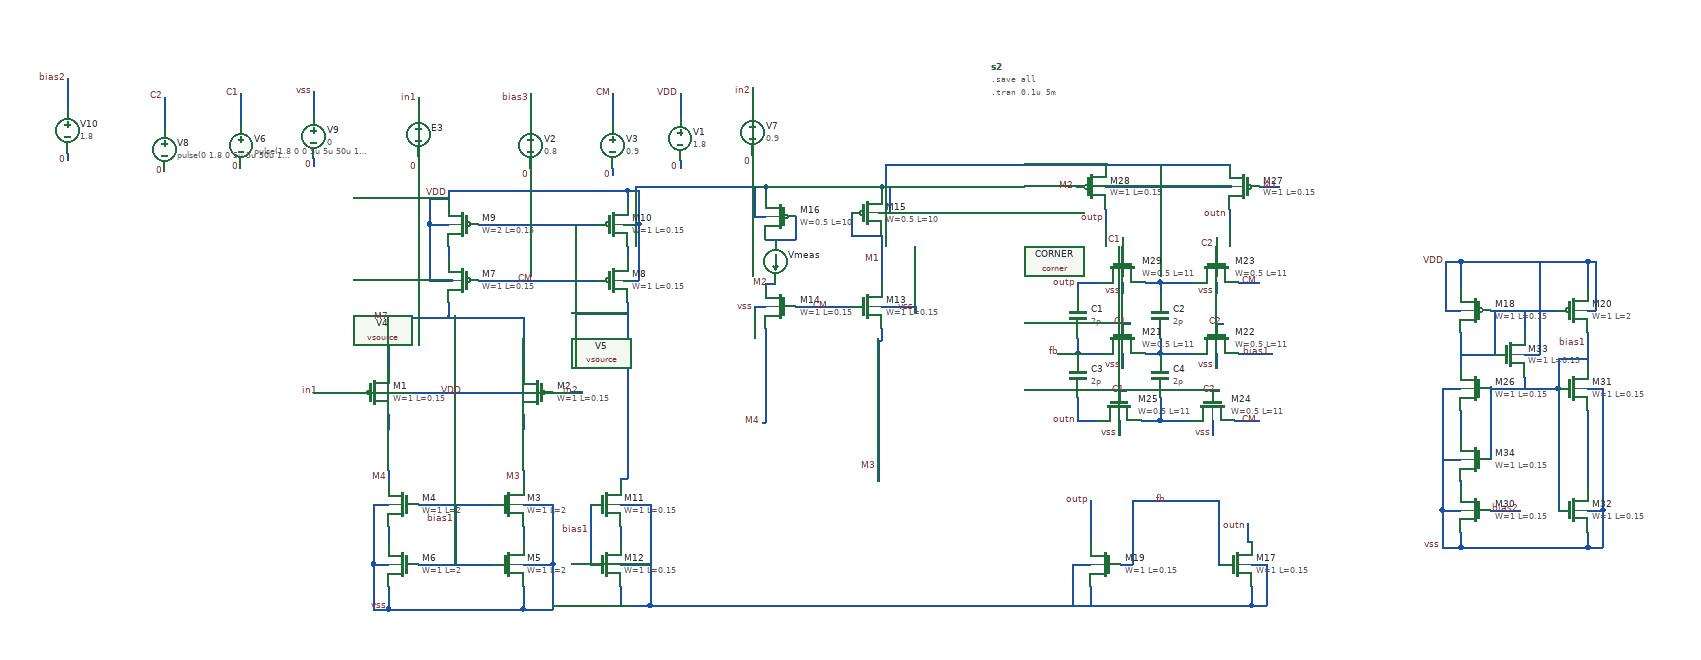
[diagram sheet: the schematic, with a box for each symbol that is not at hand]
v {xschem version=3.1.0 file_version=1.2
}
G {}
K {}
V {}
S {}
E {}
N -190 -670 -190 -660 {
lab=0}
N -390 -660 -390 -650 {
lab=0}
N -390 -760 -390 -720 {
lab=bias3}
N -280 -660 -280 -650 {
lab=0}
N -280 -760 -280 -720 {
lab=CM}
N -190 -760 -190 -730 {
lab=VDD}
N -540 -675 -540 -650 {
lab=0}
N -540 -755 -540 -735 {
lab=in1}
N -92.5 -677.5 -92.5 -667.5 {
lab=0}
N -92.5 -767.5 -92.5 -737.5 {
lab=in2}
N -680 -672.5 -680 -662.5 {
lab=0}
N -680 -762.5 -680 -732.5 {
lab=vss}
N -580 -460 -580 -390 {
lab=M7}
N -580 -460 -400 -460 {
lab=M7}
N -400 -460 -400 -390 {
lab=M7}
N -500 -480 -500 -460 {
lab=M7}
N -540 -210 -440 -210 {
lab=bias1}
N -540 -130 -440 -130 {
lab=bias1}
N -580 -180 -580 -160 {
lab=#net1}
N -400 -180 -400 -160 {
lab=#net2}
N -600 -210 -580 -210 {
lab=vss}
N -600 -210 -600 -130 {
lab=vss}
N -600 -130 -580 -130 {
lab=vss}
N -400 -210 -360 -210 {
lab=vss}
N -360 -210 -360 -130 {
lab=vss}
N -400 -130 -360 -130 {
lab=vss}
N -580 -100 -580 -70 {
lab=vss}
N -580 -70 -400 -70 {
lab=vss}
N -400 -100 -400 -70 {
lab=vss}
N -490 -210 -490 -130 {
lab=bias1}
N -680 -360 -620 -360 {
lab=in1}
N -360 -360 -320 -360 {
lab=in2}
N -600 -130 -600 -80 {
lab=vss}
N -600 -80 -600 -70 {
lab=vss}
N -600 -70 -580 -70 {
lab=vss}
N -360 -130 -360 -70 {
lab=vss}
N -400 -70 -360 -70 {
lab=vss}
N -580 -330 -580 -310 {
lab=#net3}
N -580 -250 -580 -240 {
lab=M4}
N -580 -255 -580 -250 {
lab=M4}
N -400 -330 -400 -310 {
lab=#net4}
N -400 -250 -400 -240 {
lab=M3}
N -400 -255 -400 -250 {
lab=M3}
N -525 -510 -495 -510 {
lab=VDD}
N -525 -555 -525 -510 {
lab=VDD}
N -460 -510 -300 -510 {
lab=CM}
N -500 -555 -500 -540 {
lab=#net5}
N -460 -585 -300 -585 {
lab=#net6}
N -500 -630 -500 -615 {
lab=VDD}
N -500 -630 -260 -630 {
lab=VDD}
N -260 -630 -260 -615 {
lab=VDD}
N -265 -585 -245 -585 {
lab=VDD}
N -245 -630 -245 -585 {
lab=VDD}
N -260 -630 -245 -630 {
lab=VDD}
N -260 -555 -260 -540 {
lab=#net7}
N -265 -510 -245 -510 {
lab=VDD}
N -245 -585 -245 -510 {
lab=VDD}
N -525 -585 -500 -585 {
lab=VDD}
N -525 -585 -525 -555 {
lab=VDD}
N -525 -620 -525 -585 {
lab=VDD}
N -525 -620 -500 -620 {
lab=VDD}
N -270 -180 -270 -160 {
lab=#net8}
N -270 -100 -270 -75 {
lab=vss}
N -360 -75 -270 -75 {
lab=vss}
N -270 -210 -230 -210 {
lab=vss}
N -230 -210 -230 -75 {
lab=vss}
N -275 -75 -230 -75 {
lab=vss}
N -270 -130 -230 -130 {
lab=vss}
N -310 -210 -310 -130 {
lab=bias1}
N -260 -480 -260 -245 {
lab=#net6}
N -270 -245 -260 -245 {
lab=#net6}
N -270 -245 -270 -240 {
lab=#net6}
N -330 -585 -330 -465 {
lab=#net6}
N -330 -465 -260 -465 {
lab=#net6}
N -75 -445 -75 -440 {
lab=M4}
N 80 -445 80 -430 {
lab=M3}
N -90 -475 -75 -475 {
lab=vss}
N -90 -475 -90 -470 {
lab=vss}
N 80 -475 125 -475 {
lab=vss}
N 125 -475 125 -465 {
lab=vss}
N -35 -475 40 -475 {
lab=CM}
N -35 -595 -35 -565 {
lab=#net9}
N -75 -565 -35 -565 {
lab=#net9}
N -75 -635 -75 -625 {
lab=VDD}
N -75 -635 80 -635 {
lab=VDD}
N 80 -635 80 -630 {
lab=VDD}
N 75 -600 90 -600 {
lab=VDD}
N 90 -635 90 -600 {
lab=VDD}
N 80 -635 90 -635 {
lab=VDD}
N -90 -595 -75 -595 {
lab=VDD}
N -90 -635 -90 -595 {
lab=VDD}
N -90 -635 -75 -635 {
lab=VDD}
N 40 -600 40 -570 {
lab=M1}
N 40 -570 80 -570 {
lab=M1}
N 80 -570 80 -505 {
lab=M1}
N -250 -635 -85 -635 {
lab=VDD}
N -250 -635 -250 -630 {
lab=VDD}
N 75 -430 75 -255 {
lab=M3}
N 75 -430 80 -430 {
lab=M3}
N 75 -255 75 -240 {
lab=M3}
N -75 -440 -75 -325 {
lab=M4}
N -80 -320 -75 -320 {
lab=M4}
N -75 -325 -75 -320 {
lab=M4}
N -580 -360 -395 -360 {
lab=VDD}
N -230 -75 575 -75 {
lab=vss}
N 575 -100 575 -75 {
lab=vss}
N 360 -100 360 -75 {
lab=vss}
N 400 -130 415 -130 {
lab=fb}
N 415 -215 415 -130 {
lab=fb}
N 360 -185 360 -160 {
lab=outp}
N 335 -130 360 -130 {
lab=vss}
N 575 -75 595 -75 {
lab=vss}
N 575 -130 595 -130 {
lab=vss}
N 570 -185 570 -160 {
lab=outn}
N 570 -160 575 -160 {
lab=outn}
N 530 -215 530 -130 {
lab=fb}
N 530 -130 535 -130 {
lab=fb}
N 415 -215 530 -215 {
lab=fb}
N 585 -635 612.5 -635 {
lab=M1}
N 380 -665 545 -665 {
lab=VDD}
N 380 -635 547.5 -635 {
lab=VDD}
N 452.5 -665 452.5 -635 {
lab=VDD}
N 85 -665 382.5 -665 {
lab=VDD}
N 85 -665 85 -635 {
lab=VDD}
N 380 -605 380 -582.5 {
lab=outp}
N 545 -605 545 -585 {
lab=outn}
N -777.5 -760 -777.5 -720 {
lab=C1}
N -880 -755 -880 -715 {
lab=C2}
N -75 -505 -62.5 -505 {
lab=M2}
N 342.5 -432.5 342.5 -412.5 {
lab=fb}
N 452.5 -432.5 452.5 -412.5 {
lab=#net10}
N 342.5 -352.5 342.5 -322.5 {
lab=outn}
N 342.5 -322.5 367.5 -322.5 {
lab=outn}
N 427.5 -322.5 452.5 -322.5 {
lab=#net11}
N 452.5 -352.5 452.5 -322.5 {
lab=#net11}
N 402.5 -412.5 402.5 -392.5 {
lab=vss}
N 432.5 -412.5 452.5 -412.5 {
lab=#net10}
N 342.5 -412.5 372.5 -412.5 {
lab=fb}
N 397.5 -322.5 397.5 -302.5 {
lab=vss}
N 397.5 -362.5 407.5 -362.5 {
lab=C1}
N 402.5 -452.5 412.5 -452.5 {
lab=C1}
N 342.5 -507.5 342.5 -492.5 {
lab=outp}
N 342.5 -507.5 372.5 -507.5 {
lab=outp}
N 432.5 -507.5 452.5 -507.5 {
lab=#net12}
N 452.5 -507.5 452.5 -492.5 {
lab=#net12}
N 402.5 -507.5 402.5 -492.5 {
lab=vss}
N 402.5 -567.5 402.5 -547.5 {
lab=C1}
N 527.5 -412.5 527.5 -392.5 {
lab=vss}
N 522.5 -322.5 522.5 -302.5 {
lab=vss}
N 522.5 -362.5 532.5 -362.5 {
lab=C2}
N 527.5 -452.5 537.5 -452.5 {
lab=C2}
N 527.5 -507.5 527.5 -492.5 {
lab=vss}
N 527.5 -567.5 527.5 -547.5 {
lab=C2}
N 452.5 -322.5 492.5 -322.5 {
lab=#net11}
N 452.5 -412.5 497.5 -412.5 {
lab=#net10}
N 452.5 -507.5 497.5 -507.5 {
lab=#net12}
N 315 -412.5 342.5 -412.5 {
lab=fb}
N 552.5 -322.5 557.5 -322.5 {
lab=CM}
N 557.5 -322.5 585 -322.5 {
lab=CM}
N 557.5 -507.5 585 -507.5 {
lab=CM}
N 557.5 -412.5 577.5 -412.5 {
lab=bias1}
N 577.5 -412.5 602.5 -412.5 {
lab=bias1}
N 595 -130 595 -75 {
lab=vss}
N 335 -130 335 -75 {
lab=vss}
N 360 -215 360 -185 {
lab=outp}
N 855 -535 855 -500 {
lab=VDD}
N 855 -535 1025 -535 {
lab=VDD}
N 1025 -535 1025 -505 {
lab=VDD}
N 1025 -505 1025 -500 {
lab=VDD}
N 1025 -440 1025 -395 {
lab=bias1}
N 1025 -172.5 1025 -152.5 {
lab=vss}
N 855 -152.5 1025 -152.5 {
lab=vss}
N 855 -172.5 855 -152.5 {
lab=vss}
N 855 -440 855 -395 {
lab=#net13}
N 895 -470 985 -470 {
lab=#net13}
N 940 -470 940 -440 {
lab=#net13}
N 900 -470 900 -410 {
lab=#net13}
N 855 -410 900 -410 {
lab=#net13}
N 895 -365 985 -365 {
lab=bias1}
N 940 -380 940 -365 {
lab=bias1}
N 985 -365 985 -260 {
lab=bias1}
N 985 -405 985 -365 {
lab=bias1}
N 985 -405 1025 -405 {
lab=bias1}
N 940 -410 960 -410 {
lab=VDD}
N 960 -535 960 -410 {
lab=VDD}
N 1025 -470 1035 -470 {
lab=VDD}
N 1035 -535 1035 -470 {
lab=VDD}
N 1025 -535 1035 -535 {
lab=VDD}
N 835 -470 855 -470 {
lab=VDD}
N 835 -535 835 -470 {
lab=VDD}
N 835 -535 855 -535 {
lab=VDD}
N 830 -365 855 -365 {
lab=vss}
N 830 -365 830 -260 {
lab=vss}
N 830 -202.5 855 -202.5 {
lab=vss}
N 830 -202.5 830 -152.5 {
lab=vss}
N 830 -152.5 855 -152.5 {
lab=vss}
N 1025 -365 1045 -365 {
lab=vss}
N 1045 -365 1045 -260 {
lab=vss}
N 1025 -202.5 1045 -202.5 {
lab=vss}
N 1045 -202.5 1045 -152.5 {
lab=vss}
N 1025 -152.5 1045 -152.5 {
lab=vss}
N -1010 -680 -1010 -670 {
lab=0}
N -1010 -780 -1010 -740 {
lab=bias2}
N 895 -202.5 935 -202.5 {
lab=bias2}
N 855 -242.5 855 -232.5 {
lab=#net14}
N 830 -260 830 -202.5 {
lab=vss}
N 830 -270 855 -270 {
lab=vss}
N 895 -367.5 895 -270 {
lab=bias1}
N 985 -260 985 -205 {
lab=bias1}
N 1045 -262.5 1045 -202.5 {
lab=vss}
N 1025 -335 1025 -232.5 {
lab=#net15}
N 855 -335 855 -300 {
lab=#net16}
N 985 -205 985 -202.5 {
lab=bias1}
C {devices/vsource.sym} -190 -700 0 0 {name=V1 value=1.8}
C {devices/lab_pin.sym} -190 -660 0 0 {name=p5 sig_type=std_logic lab=0}
C {devices/vsource.sym} -390 -690 0 0 {name=V2 value=0.8}
C {devices/lab_pin.sym} -390 -650 0 0 {name=p9 sig_type=std_logic lab=0}
C {devices/lab_pin.sym} 1025 -425 0 0 {name=p10 sig_type=std_logic lab=bias1}
C {devices/vsource.sym} -280 -690 0 0 {name=V3 value=0.9}
C {devices/lab_pin.sym} -280 -650 0 0 {name=p11 sig_type=std_logic lab=0}
C {devices/lab_pin.sym} -280 -760 0 0 {name=p12 sig_type=std_logic lab=CM}
C {devices/lab_pin.sym} -190 -760 0 0 {name=p16 sig_type=std_logic lab=VDD}
C {sky130_fd_pr/corner.sym} 45 -815 0 0 {name=CORNER only_toplevel=false corner=ss}
C {devices/code_shown.sym} 227.5 -795 0 0 {name=s2 only_toplevel=false value="
.save all
.tran 0.1u 5m
"}
C {devices/lab_pin.sym} -540 -660 0 0 {name=p8 sig_type=std_logic lab=0}
C {devices/lab_pin.sym} -540 -752.5 0 0 {name=p18 sig_type=std_logic lab=in1}
C {devices/vsource_arith.sym} -540 -705 0 0 {name=E3 VOL="'0.9+0.2*cos(2*pi*time*1e3))'"}
C {devices/vsource.sym} -92.5 -707.5 0 0 {name=V7 value=0.9}
C {devices/lab_pin.sym} -92.5 -667.5 0 0 {name=p26 sig_type=std_logic lab=0}
C {devices/lab_pin.sym} -92.5 -762.5 0 0 {name=p20 sig_type=std_logic lab=in2}
C {devices/vsource.sym} -680 -702.5 0 0 {name=V9 value=0}
C {devices/lab_pin.sym} -680 -662.5 0 0 {name=p31 sig_type=std_logic lab=0}
C {devices/lab_pin.sym} -680 -762.5 0 0 {name=p32 sig_type=std_logic lab=vss}
C {sky130_fd_pr/pfet_01v8.sym} -600 -360 0 0 {name=M1
L=0.15
W=1
nf=1
mult=10
ad="'int((nf+1)/2) * W/nf * 0.29'" 
pd="'2*int((nf+1)/2) * (W/nf + 0.29)'"
as="'int((nf+2)/2) * W/nf * 0.29'" 
ps="'2*int((nf+2)/2) * (W/nf + 0.29)'"
nrd="'0.29 / W'" nrs="'0.29 / W'"
sa=0 sb=0 sd=0
model=pfet_01v8
spiceprefix=X
}
C {sky130_fd_pr/pfet_01v8.sym} -380 -360 0 1 {name=M2
L=0.15
W=1
nf=1
mult=10
ad="'int((nf+1)/2) * W/nf * 0.29'" 
pd="'2*int((nf+1)/2) * (W/nf + 0.29)'"
as="'int((nf+2)/2) * W/nf * 0.29'" 
ps="'2*int((nf+2)/2) * (W/nf + 0.29)'"
nrd="'0.29 / W'" nrs="'0.29 / W'"
sa=0 sb=0 sd=0
model=pfet_01v8
spiceprefix=X
}
C {sky130_fd_pr/nfet_01v8.sym} -420 -210 0 0 {name=M3
L=2
W=1
nf=1 
mult=1
ad="'int((nf+1)/2) * W/nf * 0.29'" 
pd="'2*int((nf+1)/2) * (W/nf + 0.29)'"
as="'int((nf+2)/2) * W/nf * 0.29'" 
ps="'2*int((nf+2)/2) * (W/nf + 0.29)'"
nrd="'0.29 / W'" nrs="'0.29 / W'"
sa=0 sb=0 sd=0
model=nfet_01v8
spiceprefix=X
}
C {sky130_fd_pr/nfet_01v8.sym} -560 -210 0 1 {name=M4
L=2
W=1
nf=1 
mult=1
ad="'int((nf+1)/2) * W/nf * 0.29'" 
pd="'2*int((nf+1)/2) * (W/nf + 0.29)'"
as="'int((nf+2)/2) * W/nf * 0.29'" 
ps="'2*int((nf+2)/2) * (W/nf + 0.29)'"
nrd="'0.29 / W'" nrs="'0.29 / W'"
sa=0 sb=0 sd=0
model=nfet_01v8
spiceprefix=X
}
C {sky130_fd_pr/nfet_01v8.sym} -420 -130 0 0 {name=M5
L=2
W=1
nf=1 
mult=1
ad="'int((nf+1)/2) * W/nf * 0.29'" 
pd="'2*int((nf+1)/2) * (W/nf + 0.29)'"
as="'int((nf+2)/2) * W/nf * 0.29'" 
ps="'2*int((nf+2)/2) * (W/nf + 0.29)'"
nrd="'0.29 / W'" nrs="'0.29 / W'"
sa=0 sb=0 sd=0
model=nfet_01v8
spiceprefix=X
}
C {sky130_fd_pr/nfet_01v8.sym} -560 -130 0 1 {name=M6
L=2
W=1
nf=1 
mult=1
ad="'int((nf+1)/2) * W/nf * 0.29'" 
pd="'2*int((nf+1)/2) * (W/nf + 0.29)'"
as="'int((nf+2)/2) * W/nf * 0.29'" 
ps="'2*int((nf+2)/2) * (W/nf + 0.29)'"
nrd="'0.29 / W'" nrs="'0.29 / W'"
sa=0 sb=0 sd=0
model=nfet_01v8
spiceprefix=X
}
C {devices/lab_pin.sym} -500 -625 0 0 {name=p1 sig_type=std_logic lab=VDD}
C {devices/lab_pin.sym} -672.5 -360 0 0 {name=p2 sig_type=std_logic lab=in1}
C {devices/lab_pin.sym} -322.5 -360 0 0 {name=p3 sig_type=std_logic lab=in2}
C {devices/lab_pin.sym} -580 -72.5 0 0 {name=p4 sig_type=std_logic lab=vss}
C {devices/lab_pin.sym} -490 -190 0 0 {name=p6 sig_type=std_logic lab=bias1}
C {devices/vsource.sym} -580 -282.5 0 0 {name=V4 value=0}
C {devices/vsource.sym} -400 -282.5 0 0 {name=V5 value=0}
C {sky130_fd_pr/pfet_01v8.sym} -480 -510 0 1 {name=M7
L=0.15
W=1
nf=1
mult=1
ad="'int((nf+1)/2) * W/nf * 0.29'" 
pd="'2*int((nf+1)/2) * (W/nf + 0.29)'"
as="'int((nf+2)/2) * W/nf * 0.29'" 
ps="'2*int((nf+2)/2) * (W/nf + 0.29)'"
nrd="'0.29 / W'" nrs="'0.29 / W'"
sa=0 sb=0 sd=0
model=pfet_01v8
spiceprefix=X
}
C {sky130_fd_pr/pfet_01v8.sym} -280 -510 0 0 {name=M8
L=0.15
W=1
nf=1
mult=1
ad="'int((nf+1)/2) * W/nf * 0.29'" 
pd="'2*int((nf+1)/2) * (W/nf + 0.29)'"
as="'int((nf+2)/2) * W/nf * 0.29'" 
ps="'2*int((nf+2)/2) * (W/nf + 0.29)'"
nrd="'0.29 / W'" nrs="'0.29 / W'"
sa=0 sb=0 sd=0
model=pfet_01v8
spiceprefix=X
}
C {sky130_fd_pr/pfet_01v8.sym} -480 -585 0 1 {name=M9
L=0.15
W=2
nf=1
mult=1
ad="'int((nf+1)/2) * W/nf * 0.29'" 
pd="'2*int((nf+1)/2) * (W/nf + 0.29)'"
as="'int((nf+2)/2) * W/nf * 0.29'" 
ps="'2*int((nf+2)/2) * (W/nf + 0.29)'"
nrd="'0.29 / W'" nrs="'0.29 / W'"
sa=0 sb=0 sd=0
model=pfet_01v8
spiceprefix=X
}
C {sky130_fd_pr/pfet_01v8.sym} -280 -585 0 0 {name=M10
L=0.15
W=1
nf=1
mult=1
ad="'int((nf+1)/2) * W/nf * 0.29'" 
pd="'2*int((nf+1)/2) * (W/nf + 0.29)'"
as="'int((nf+2)/2) * W/nf * 0.29'" 
ps="'2*int((nf+2)/2) * (W/nf + 0.29)'"
nrd="'0.29 / W'" nrs="'0.29 / W'"
sa=0 sb=0 sd=0
model=pfet_01v8
spiceprefix=X
}
C {sky130_fd_pr/nfet_01v8.sym} -290 -210 0 0 {name=M11
L=0.15
W=1
nf=1 
mult=1
ad="'int((nf+1)/2) * W/nf * 0.29'" 
pd="'2*int((nf+1)/2) * (W/nf + 0.29)'"
as="'int((nf+2)/2) * W/nf * 0.29'" 
ps="'2*int((nf+2)/2) * (W/nf + 0.29)'"
nrd="'0.29 / W'" nrs="'0.29 / W'"
sa=0 sb=0 sd=0
model=nfet_01v8
spiceprefix=X
}
C {sky130_fd_pr/nfet_01v8.sym} -290 -130 0 0 {name=M12
L=0.15
W=1
nf=1 
mult=1
ad="'int((nf+1)/2) * W/nf * 0.29'" 
pd="'2*int((nf+1)/2) * (W/nf + 0.29)'"
as="'int((nf+2)/2) * W/nf * 0.29'" 
ps="'2*int((nf+2)/2) * (W/nf + 0.29)'"
nrd="'0.29 / W'" nrs="'0.29 / W'"
sa=0 sb=0 sd=0
model=nfet_01v8
spiceprefix=X
}
C {devices/lab_pin.sym} -310 -175 0 0 {name=p7 sig_type=std_logic lab=bias1}
C {devices/lab_pin.sym} -385 -510 0 0 {name=p13 sig_type=std_logic lab=CM}
C {sky130_fd_pr/nfet_01v8.sym} 60 -475 0 0 {name=M13
L=0.15
W=1
nf=1 
mult=1
ad="'int((nf+1)/2) * W/nf * 0.29'" 
pd="'2*int((nf+1)/2) * (W/nf + 0.29)'"
as="'int((nf+2)/2) * W/nf * 0.29'" 
ps="'2*int((nf+2)/2) * (W/nf + 0.29)'"
nrd="'0.29 / W'" nrs="'0.29 / W'"
sa=0 sb=0 sd=0
model=nfet_01v8
spiceprefix=X
}
C {sky130_fd_pr/nfet_01v8.sym} -55 -475 0 1 {name=M14
L=0.15
W=1
nf=1 
mult=1
ad="'int((nf+1)/2) * W/nf * 0.29'" 
pd="'2*int((nf+1)/2) * (W/nf + 0.29)'"
as="'int((nf+2)/2) * W/nf * 0.29'" 
ps="'2*int((nf+2)/2) * (W/nf + 0.29)'"
nrd="'0.29 / W'" nrs="'0.29 / W'"
sa=0 sb=0 sd=0
model=nfet_01v8
spiceprefix=X
}
C {devices/lab_pin.sym} -90 -472.5 0 0 {name=p14 sig_type=std_logic lab=vss}
C {devices/lab_pin.sym} 125 -472.5 0 0 {name=p15 sig_type=std_logic lab=vss}
C {devices/lab_pin.sym} 10 -475 0 0 {name=p17 sig_type=std_logic lab=CM}
C {sky130_fd_pr/pfet_01v8.sym} 60 -600 0 0 {name=M15
L=10
W=0.5
nf=1
mult=1
ad="'int((nf+1)/2) * W/nf * 0.29'" 
pd="'2*int((nf+1)/2) * (W/nf + 0.29)'"
as="'int((nf+2)/2) * W/nf * 0.29'" 
ps="'2*int((nf+2)/2) * (W/nf + 0.29)'"
nrd="'0.29 / W'" nrs="'0.29 / W'"
sa=0 sb=0 sd=0
model=pfet_01v8
spiceprefix=X
}
C {sky130_fd_pr/pfet_01v8.sym} -55 -595 0 1 {name=M16
L=10
W=0.5
nf=1
mult=1
ad="'int((nf+1)/2) * W/nf * 0.29'" 
pd="'2*int((nf+1)/2) * (W/nf + 0.29)'"
as="'int((nf+2)/2) * W/nf * 0.29'" 
ps="'2*int((nf+2)/2) * (W/nf + 0.29)'"
nrd="'0.29 / W'" nrs="'0.29 / W'"
sa=0 sb=0 sd=0
model=pfet_01v8
spiceprefix=X
}
C {devices/lab_pin.sym} 75 -260 0 0 {name=p22 sig_type=std_logic lab=M3}
C {devices/lab_pin.sym} -400 -245 0 0 {name=p23 sig_type=std_logic lab=M3}
C {devices/lab_pin.sym} -80 -320 0 0 {name=p24 sig_type=std_logic lab=M4}
C {devices/lab_pin.sym} -580 -245 0 0 {name=p25 sig_type=std_logic lab=M4}
C {devices/lab_pin.sym} -480 -360 0 0 {name=p27 sig_type=std_logic lab=VDD}
C {sky130_fd_pr/nfet_01v8.sym} 555 -130 0 0 {name=M17
L=0.15
W=1
nf=1 
mult=1
ad="'int((nf+1)/2) * W/nf * 0.29'" 
pd="'2*int((nf+1)/2) * (W/nf + 0.29)'"
as="'int((nf+2)/2) * W/nf * 0.29'" 
ps="'2*int((nf+2)/2) * (W/nf + 0.29)'"
nrd="'0.29 / W'" nrs="'0.29 / W'"
sa=0 sb=0 sd=0
model=nfet_01v8
spiceprefix=X
}
C {sky130_fd_pr/nfet_01v8.sym} 380 -130 0 1 {name=M19
L=0.15
W=1
nf=1 
mult=1
ad="'int((nf+1)/2) * W/nf * 0.29'" 
pd="'2*int((nf+1)/2) * (W/nf + 0.29)'"
as="'int((nf+2)/2) * W/nf * 0.29'" 
ps="'2*int((nf+2)/2) * (W/nf + 0.29)'"
nrd="'0.29 / W'" nrs="'0.29 / W'"
sa=0 sb=0 sd=0
model=nfet_01v8
spiceprefix=X
}
C {devices/lab_pin.sym} 360 -215 0 0 {name=p48 sig_type=std_logic lab=outp}
C {devices/lab_pin.sym} 570 -180 0 0 {name=p49 sig_type=std_logic lab=outn}
C {sky130_fd_pr/pfet_01v8.sym} 565 -635 0 1 {name=M27
L=0.15
W=1
nf=1
mult=1
ad="'int((nf+1)/2) * W/nf * 0.29'" 
pd="'2*int((nf+1)/2) * (W/nf + 0.29)'"
as="'int((nf+2)/2) * W/nf * 0.29'" 
ps="'2*int((nf+2)/2) * (W/nf + 0.29)'"
nrd="'0.29 / W'" nrs="'0.29 / W'"
sa=0 sb=0 sd=0
model=pfet_01v8
spiceprefix=X
}
C {sky130_fd_pr/pfet_01v8.sym} 360 -635 0 0 {name=M28
L=0.15
W=1
nf=1
mult=1
ad="'int((nf+1)/2) * W/nf * 0.29'" 
pd="'2*int((nf+1)/2) * (W/nf + 0.29)'"
as="'int((nf+2)/2) * W/nf * 0.29'" 
ps="'2*int((nf+2)/2) * (W/nf + 0.29)'"
nrd="'0.29 / W'" nrs="'0.29 / W'"
sa=0 sb=0 sd=0
model=pfet_01v8
spiceprefix=X
}
C {devices/lab_pin.sym} 340 -635 0 0 {name=p50 sig_type=std_logic lab=M2}
C {devices/lab_pin.sym} 612.5 -635 0 0 {name=p51 sig_type=std_logic lab=M1}
C {devices/lab_pin.sym} 545 -597.5 0 0 {name=p54 sig_type=std_logic lab=outn}
C {devices/lab_pin.sym} 380 -592.5 0 0 {name=p52 sig_type=std_logic lab=outp}
C {devices/lab_pin.sym} -777.5 -760 0 0 {name=p19 sig_type=std_logic lab=C1}
C {devices/vsource.sym} -777.5 -690 0 0 {name=V6 value="pulse(1.8 0 0 5u 5u 50u 100u)"}
C {devices/lab_pin.sym} -777.5 -660 0 0 {name=p55 sig_type=std_logic lab=0}
C {devices/lab_pin.sym} -880 -755 0 0 {name=p56 sig_type=std_logic lab=C2}
C {devices/vsource.sym} -880 -685 0 0 {name=V8 value="pulse(0 1.8 0 5u 5u 50u 100u)"}
C {devices/lab_pin.sym} -880 -655 0 0 {name=p57 sig_type=std_logic lab=0}
C {devices/lab_pin.sym} 80 -537.5 0 0 {name=p21 sig_type=std_logic lab=M1}
C {devices/lab_pin.sym} -70 -505 0 0 {name=p53 sig_type=std_logic lab=M2}
C {devices/ammeter.sym} -62.5 -535 0 0 {name=Vmeas}
C {devices/capa.sym} 342.5 -462.5 0 0 {name=C1
m=1
value=2p
footprint=1206
device="ceramic capacitor"}
C {devices/capa.sym} 452.5 -462.5 0 0 {name=C2
m=1
value=2p
footprint=1206
device="ceramic capacitor"}
C {devices/capa.sym} 342.5 -382.5 0 0 {name=C3
m=1
value=2p
footprint=1206
device="ceramic capacitor"}
C {devices/capa.sym} 452.5 -382.5 0 0 {name=C4
m=1
value=2p
footprint=1206
device="ceramic capacitor"}
C {devices/lab_pin.sym} 402.5 -395 0 0 {name=p29 sig_type=std_logic lab=vss}
C {devices/lab_pin.sym} 397.5 -305 0 0 {name=p30 sig_type=std_logic lab=vss}
C {devices/lab_pin.sym} 402.5 -495 0 0 {name=p33 sig_type=std_logic lab=vss}
C {devices/lab_pin.sym} 527.5 -395 0 0 {name=p34 sig_type=std_logic lab=vss}
C {devices/lab_pin.sym} 522.5 -305 0 0 {name=p35 sig_type=std_logic lab=vss}
C {devices/lab_pin.sym} 527.5 -495 0 0 {name=p36 sig_type=std_logic lab=vss}
C {devices/lab_pin.sym} 407.5 -362.5 0 0 {name=p37 sig_type=std_logic lab=C1}
C {devices/lab_pin.sym} 410 -452.5 0 0 {name=p38 sig_type=std_logic lab=C1}
C {devices/lab_pin.sym} 402.5 -562.5 0 0 {name=p39 sig_type=std_logic lab=C1}
C {devices/lab_pin.sym} 527.5 -557.5 0 0 {name=p40 sig_type=std_logic lab=C2}
C {devices/lab_pin.sym} 537.5 -452.5 0 0 {name=p41 sig_type=std_logic lab=C2}
C {devices/lab_pin.sym} 530 -362.5 0 0 {name=p42 sig_type=std_logic lab=C2}
C {devices/lab_pin.sym} 585 -322.5 0 0 {name=p43 sig_type=std_logic lab=CM}
C {devices/lab_pin.sym} 585 -507.5 0 0 {name=p44 sig_type=std_logic lab=CM}
C {devices/lab_pin.sym} 602.5 -412.5 0 0 {name=p45 sig_type=std_logic lab=bias1}
C {devices/lab_pin.sym} 320 -412.5 0 0 {name=p46 sig_type=std_logic lab=fb}
C {devices/lab_pin.sym} 342.5 -322.5 0 0 {name=p47 sig_type=std_logic lab=outn}
C {devices/lab_pin.sym} 342.5 -505 0 0 {name=p58 sig_type=std_logic lab=outp}
C {sky130_fd_pr/nfet_01v8.sym} 402.5 -527.5 1 0 {name=M29
L=11
W=0.5
nf=1
mult=1
ad="'int((nf+1)/2) * W/nf * 0.29'" 
pd="'2*int((nf+1)/2) * (W/nf + 0.29)'"
as="'int((nf+2)/2) * W/nf * 0.29'" 
ps="'2*int((nf+2)/2) * (W/nf + 0.29)'"
nrd="'0.29 / W'" nrs="'0.29 / W'"
sa=0 sb=0 sd=0
model=nfet_01v8_lvt
spiceprefix=X
}
C {sky130_fd_pr/nfet_01v8.sym} 527.5 -527.5 1 0 {name=M23
L=11
W=0.5
nf=1
mult=1
ad="'int((nf+1)/2) * W/nf * 0.29'" 
pd="'2*int((nf+1)/2) * (W/nf + 0.29)'"
as="'int((nf+2)/2) * W/nf * 0.29'" 
ps="'2*int((nf+2)/2) * (W/nf + 0.29)'"
nrd="'0.29 / W'" nrs="'0.29 / W'"
sa=0 sb=0 sd=0
model=nfet_01v8_lvt
spiceprefix=X
}
C {sky130_fd_pr/nfet_01v8.sym} 522.5 -342.5 1 0 {name=M24
L=11
W=0.5
nf=1
mult=1
ad="'int((nf+1)/2) * W/nf * 0.29'" 
pd="'2*int((nf+1)/2) * (W/nf + 0.29)'"
as="'int((nf+2)/2) * W/nf * 0.29'" 
ps="'2*int((nf+2)/2) * (W/nf + 0.29)'"
nrd="'0.29 / W'" nrs="'0.29 / W'"
sa=0 sb=0 sd=0
model=nfet_01v8_lvt
spiceprefix=X
}
C {sky130_fd_pr/nfet_01v8.sym} 402.5 -432.5 1 0 {name=M21
L=11
W=0.5
nf=1
mult=1
ad="'int((nf+1)/2) * W/nf * 0.29'" 
pd="'2*int((nf+1)/2) * (W/nf + 0.29)'"
as="'int((nf+2)/2) * W/nf * 0.29'" 
ps="'2*int((nf+2)/2) * (W/nf + 0.29)'"
nrd="'0.29 / W'" nrs="'0.29 / W'"
sa=0 sb=0 sd=0
model=nfet_01v8_lvt
spiceprefix=X
}
C {sky130_fd_pr/nfet_01v8.sym} 527.5 -432.5 1 0 {name=M22
L=11
W=0.5
nf=1
mult=1
ad="'int((nf+1)/2) * W/nf * 0.29'" 
pd="'2*int((nf+1)/2) * (W/nf + 0.29)'"
as="'int((nf+2)/2) * W/nf * 0.29'" 
ps="'2*int((nf+2)/2) * (W/nf + 0.29)'"
nrd="'0.29 / W'" nrs="'0.29 / W'"
sa=0 sb=0 sd=0
model=nfet_01v8_lvt
spiceprefix=X
}
C {sky130_fd_pr/nfet_01v8.sym} 397.5 -342.5 1 0 {name=M25
L=11
W=0.5
nf=1
mult=1
ad="'int((nf+1)/2) * W/nf * 0.29'" 
pd="'2*int((nf+1)/2) * (W/nf + 0.29)'"
as="'int((nf+2)/2) * W/nf * 0.29'" 
ps="'2*int((nf+2)/2) * (W/nf + 0.29)'"
nrd="'0.29 / W'" nrs="'0.29 / W'"
sa=0 sb=0 sd=0
model=nfet_01v8_lvt
spiceprefix=X
}
C {sky130_fd_pr/pfet_01v8.sym} 875 -470 0 1 {name=M18
L=0.15
W=1
nf=1
mult=1
ad="'int((nf+1)/2) * W/nf * 0.29'" 
pd="'2*int((nf+1)/2) * (W/nf + 0.29)'"
as="'int((nf+2)/2) * W/nf * 0.29'" 
ps="'2*int((nf+2)/2) * (W/nf + 0.29)'"
nrd="'0.29 / W'" nrs="'0.29 / W'"
sa=0 sb=0 sd=0
model=pfet_01v8
spiceprefix=X
}
C {sky130_fd_pr/pfet_01v8.sym} 1005 -470 0 0 {name=M20
L=2
W=1
nf=1
mult=1
ad="'int((nf+1)/2) * W/nf * 0.29'" 
pd="'2*int((nf+1)/2) * (W/nf + 0.29)'"
as="'int((nf+2)/2) * W/nf * 0.29'" 
ps="'2*int((nf+2)/2) * (W/nf + 0.29)'"
nrd="'0.29 / W'" nrs="'0.29 / W'"
sa=0 sb=0 sd=0
model=pfet_01v8
spiceprefix=X
}
C {sky130_fd_pr/nfet_01v8.sym} 875 -365 0 1 {name=M26
L=0.15
W=1
nf=1
mult=1
ad="'int((nf+1)/2) * W/nf * 0.29'" 
pd="'2*int((nf+1)/2) * (W/nf + 0.29)'"
as="'int((nf+2)/2) * W/nf * 0.29'" 
ps="'2*int((nf+2)/2) * (W/nf + 0.29)'"
nrd="'0.29 / W'" nrs="'0.29 / W'"
sa=0 sb=0 sd=0
model=pfet_01v8
spiceprefix=X
}
C {sky130_fd_pr/nfet_01v8.sym} 875 -202.5 0 1 {name=M30
L=0.15
W=1
nf=1
mult=1
ad="'int((nf+1)/2) * W/nf * 0.29'" 
pd="'2*int((nf+1)/2) * (W/nf + 0.29)'"
as="'int((nf+2)/2) * W/nf * 0.29'" 
ps="'2*int((nf+2)/2) * (W/nf + 0.29)'"
nrd="'0.29 / W'" nrs="'0.29 / W'"
sa=0 sb=0 sd=0
model=pfet_01v8
spiceprefix=X
}
C {sky130_fd_pr/nfet_01v8.sym} 1005 -365 0 0 {name=M31
L=0.15
W=1
nf=1
mult=4
ad="'int((nf+1)/2) * W/nf * 0.29'" 
pd="'2*int((nf+1)/2) * (W/nf + 0.29)'"
as="'int((nf+2)/2) * W/nf * 0.29'" 
ps="'2*int((nf+2)/2) * (W/nf + 0.29)'"
nrd="'0.29 / W'" nrs="'0.29 / W'"
sa=0 sb=0 sd=0
model=pfet_01v8
spiceprefix=X
}
C {sky130_fd_pr/nfet_01v8.sym} 1005 -202.5 0 0 {name=M32
L=0.15
W=1
nf=1
mult=4
ad="'int((nf+1)/2) * W/nf * 0.29'" 
pd="'2*int((nf+1)/2) * (W/nf + 0.29)'"
as="'int((nf+2)/2) * W/nf * 0.29'" 
ps="'2*int((nf+2)/2) * (W/nf + 0.29)'"
nrd="'0.29 / W'" nrs="'0.29 / W'"
sa=0 sb=0 sd=0
model=pfet_01v8
spiceprefix=X
}
C {sky130_fd_pr/nfet_01v8.sym} 920 -410 0 0 {name=M33
L=0.15
W=1
nf=1
mult=1
ad="'int((nf+1)/2) * W/nf * 0.29'" 
pd="'2*int((nf+1)/2) * (W/nf + 0.29)'"
as="'int((nf+2)/2) * W/nf * 0.29'" 
ps="'2*int((nf+2)/2) * (W/nf + 0.29)'"
nrd="'0.29 / W'" nrs="'0.29 / W'"
sa=0 sb=0 sd=0
model=pfet_01v8
spiceprefix=X
}
C {devices/lab_pin.sym} 830 -155 0 0 {name=p59 sig_type=std_logic lab=vss}
C {devices/lab_pin.sym} 835 -535 0 0 {name=p60 sig_type=std_logic lab=VDD}
C {devices/vsource.sym} -1010 -710 0 0 {name=V10 value=1.8}
C {devices/lab_pin.sym} -1010 -670 0 0 {name=p61 sig_type=std_logic lab=0}
C {devices/lab_pin.sym} -1010 -780 0 0 {name=p62 sig_type=std_logic lab=bias2}
C {devices/lab_pin.sym} 935 -202.5 0 0 {name=p63 sig_type=std_logic lab=bias2}
C {devices/lab_pin.sym} 462.5 -215 0 0 {name=p28 sig_type=std_logic lab=fb}
C {devices/lab_pin.sym} -390 -752.5 0 0 {name=p67 sig_type=std_logic lab=bias3}
C {sky130_fd_pr/nfet_01v8.sym} 875 -270 0 1 {name=M34
L=0.15
W=1
nf=1
mult=1
ad="'int((nf+1)/2) * W/nf * 0.29'" 
pd="'2*int((nf+1)/2) * (W/nf + 0.29)'"
as="'int((nf+2)/2) * W/nf * 0.29'" 
ps="'2*int((nf+2)/2) * (W/nf + 0.29)'"
nrd="'0.29 / W'" nrs="'0.29 / W'"
sa=0 sb=0 sd=0
model=pfet_01v8
spiceprefix=X
}
C {devices/lab_pin.sym} -577.5 -460 0 0 {name=p64 sig_type=std_logic lab=M7}
